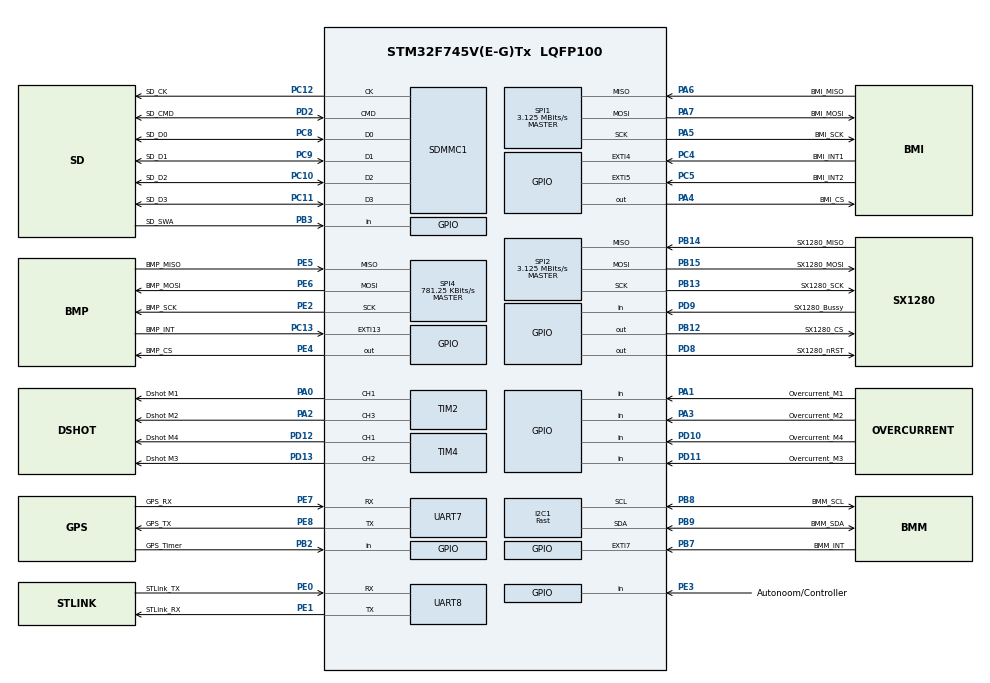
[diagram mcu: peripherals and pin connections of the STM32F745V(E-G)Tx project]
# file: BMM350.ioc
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CORTEX_M7.default_mode_Activation=1
Dma.Request0=TIM4_CH1
Dma.Request1=TIM4_CH2
Dma.Request2=TIM2_UP/CH3
Dma.Request3=TIM2_CH1
Dma.TIM2_CH1.3.Direction=DMA_MEMORY_TO_PERIPH
Dma.TIM2_CH1.3.FIFOMode=DMA_FIFOMODE_DISABLE
Dma.TIM2_CH1.3.Instance=DMA1_Stream5
Dma.TIM2_CH1.3.MemDataAlignment=DMA_MDATAALIGN_WORD
Dma.TIM2_CH1.3.MemInc=DMA_MINC_ENABLE
Dma.TIM2_CH1.3.Mode=DMA_NORMAL
Dma.TIM2_CH1.3.PeriphDataAlignment=DMA_PDATAALIGN_WORD
Dma.TIM2_CH1.3.PeriphInc=DMA_PINC_DISABLE
Dma.TIM2_CH1.3.Priority=DMA_PRIORITY_VERY_HIGH
Dma.TIM2_UP/CH3.2.Direction=DMA_MEMORY_TO_PERIPH
Dma.TIM2_UP/CH3.2.FIFOMode=DMA_FIFOMODE_DISABLE
Dma.TIM2_UP/CH3.2.Instance=DMA1_Stream1
Dma.TIM2_UP/CH3.2.MemDataAlignment=DMA_MDATAALIGN_WORD
Dma.TIM2_UP/CH3.2.MemInc=DMA_MINC_ENABLE
Dma.TIM2_UP/CH3.2.Mode=DMA_NORMAL
Dma.TIM2_UP/CH3.2.PeriphDataAlignment=DMA_PDATAALIGN_WORD
Dma.TIM2_UP/CH3.2.PeriphInc=DMA_PINC_DISABLE
Dma.TIM2_UP/CH3.2.Priority=DMA_PRIORITY_VERY_HIGH
Dma.TIM4_CH1.0.Direction=DMA_MEMORY_TO_PERIPH
Dma.TIM4_CH1.0.FIFOMode=DMA_FIFOMODE_DISABLE
Dma.TIM4_CH1.0.Instance=DMA1_Stream0
Dma.TIM4_CH1.0.MemDataAlignment=DMA_MDATAALIGN_HALFWORD
Dma.TIM4_CH1.0.MemInc=DMA_MINC_ENABLE
Dma.TIM4_CH1.0.Mode=DMA_NORMAL
Dma.TIM4_CH1.0.PeriphDataAlignment=DMA_PDATAALIGN_HALFWORD
Dma.TIM4_CH1.0.PeriphInc=DMA_PINC_DISABLE
Dma.TIM4_CH1.0.Priority=DMA_PRIORITY_VERY_HIGH
Dma.TIM4_CH2.1.Direction=DMA_MEMORY_TO_PERIPH
Dma.TIM4_CH2.1.FIFOMode=DMA_FIFOMODE_DISABLE
Dma.TIM4_CH2.1.Instance=DMA1_Stream3
Dma.TIM4_CH2.1.MemDataAlignment=DMA_MDATAALIGN_HALFWORD
Dma.TIM4_CH2.1.MemInc=DMA_MINC_ENABLE
Dma.TIM4_CH2.1.Mode=DMA_NORMAL
Dma.TIM4_CH2.1.PeriphDataAlignment=DMA_PDATAALIGN_HALFWORD
Dma.TIM4_CH2.1.PeriphInc=DMA_PINC_DISABLE
Dma.TIM4_CH2.1.Priority=DMA_PRIORITY_VERY_HIGH
FATFS.BSP.number=1
FATFS0.BSP.STBoard=false
FATFS0.BSP.api=Unknown
FATFS0.BSP.instance=PB3
FATFS0.BSP.ip=GPIO
FATFS0.BSP.mode=Input
FATFS0.BSP.name=Detect_SDIO
FATFS0.BSP.solution=PB3
I2C1.I2C_Speed_Mode=I2C_Fast
I2C1.Timing=0x00000108
Mcu.Family=STM32F7
Mcu.Name=STM32F745V(E-G)Tx
Mcu.Package=LQFP100
NVIC.DMA1_Stream0_IRQn=true\:0\:0\:false\:false\:true\:false\:true\:true
NVIC.DMA1_Stream1_IRQn=true\:0\:0\:false\:false\:true\:false\:true\:true
NVIC.DMA1_Stream3_IRQn=true\:0\:0\:false\:false\:true\:false\:true\:true
NVIC.DMA1_Stream5_IRQn=true\:0\:0\:false\:false\:true\:false\:true\:true
NVIC.EXTI15_10_IRQn=true\:0\:0\:false\:false\:true\:true\:true\:true
NVIC.EXTI4_IRQn=true\:3\:0\:true\:false\:true\:true\:true\:true
NVIC.EXTI9_5_IRQn=true\:3\:0\:true\:false\:true\:true\:true\:true
NVIC.PriorityGroup=NVIC_PRIORITYGROUP_4
PA0/WKUP.GPIO_Label=Dshot M1
PA0/WKUP.Signal=S_TIM2_CH1_ETR
PA1.GPIO_Label=Overcurrent_M1
PA1.Signal=GPIO_Input
PA13.GPIO_Label=STLink_DIO
PA13.Mode=Serial_Wire
PA13.Signal=SYS_JTMS-SWDIO
PA14.GPIO_Label=STLink_CLK
PA14.Mode=Serial_Wire
PA14.Signal=SYS_JTCK-SWCLK
PA2.GPIO_Label=Dshot M2
PA2.Signal=S_TIM2_CH3
PA3.GPIO_Label=Overcurrent_M2
PA3.Signal=GPIO_Input
PA4.GPIO_Label=BMI_CS
PA4.Signal=GPIO_Output
PA5.GPIO_Label=BMI_SCK
PA5.Mode=Full_Duplex_Master
PA5.Signal=SPI1_SCK
PA6.GPIO_Label=BMI_MISO
PA6.Mode=Full_Duplex_Master
PA6.Signal=SPI1_MISO
PA7.GPIO_Label=BMI_MOSI
PA7.Mode=Full_Duplex_Master
PA7.Signal=SPI1_MOSI
PB12.GPIO_Label=SX1280_CS
PB12.Signal=GPIO_Output
PB13.GPIO_Label=SX1280_SCK
PB13.Mode=Full_Duplex_Master
PB13.Signal=SPI2_SCK
PB14.GPIO_Label=SX1280_MISO
PB14.Mode=Full_Duplex_Master
PB14.Signal=SPI2_MISO
PB15.GPIO_Label=SX1280_MOSI
PB15.Mode=Full_Duplex_Master
PB15.Signal=SPI2_MOSI
PB2.GPIO_Label=GPS_Timer
PB2.Signal=GPIO_Input
PB3.GPIO_Label=SD_SWA
PB3.Signal=GPIO_Input
PB7.GPIO_Label=BMM_INT
PB7.Signal=GPXTI7
PB8.GPIO_Label=BMM_SCL
PB8.Mode=I2C
PB8.Signal=I2C1_SCL
PB9.GPIO_Label=BMM_SDA
PB9.Mode=I2C
PB9.Signal=I2C1_SDA
PC10.GPIO_Label=SD_D2
PC10.Mode=SD_4_bits_Wide_bus
PC10.Signal=SDMMC1_D2
PC11.GPIO_Label=SD_D3
PC11.Mode=SD_4_bits_Wide_bus
PC11.Signal=SDMMC1_D3
PC12.GPIO_Label=SD_CK
PC12.Mode=SD_4_bits_Wide_bus
PC12.Signal=SDMMC1_CK
PC13.GPIO_Label=BMP_INT
PC13.Signal=GPXTI13
PC4.GPIO_Label=BMI_INT1
PC4.Signal=GPXTI4
PC5.GPIO_Label=BMI_INT2
PC5.Signal=GPXTI5
PC8.GPIO_Label=SD_D0
PC8.Mode=SD_4_bits_Wide_bus
PC8.Signal=SDMMC1_D0
PC9.GPIO_Label=SD_D1
PC9.Mode=SD_4_bits_Wide_bus
PC9.Signal=SDMMC1_D1
PD10.GPIO_Label=Overcurrent_M4
PD10.Signal=GPIO_Input
PD11.GPIO_Label=Overcurrent_M3
PD11.Signal=GPIO_Input
PD12.GPIO_Label=Dshot M4
PD12.Signal=S_TIM4_CH1
PD13.GPIO_Label=Dshot M3
PD13.Signal=S_TIM4_CH2
PD2.GPIO_Label=SD_CMD
PD2.Mode=SD_4_bits_Wide_bus
PD2.Signal=SDMMC1_CMD
PD8.GPIO_Label=SX1280_nRST
PD8.Signal=GPIO_Output
PD9.GPIO_Label=SX1280_Bussy
PD9.Signal=GPIO_Input
PE0.GPIO_Label=STLink_TX
PE0.Mode=Asynchronous
PE0.Signal=UART8_RX
PE1.GPIO_Label=STLink_RX
PE1.Mode=Asynchronous
PE1.Signal=UART8_TX
PE2.GPIO_Label=BMP_SCK
PE2.Mode=Full_Duplex_Master
PE2.Signal=SPI4_SCK
PE3.GPIO_Label=Autonoom/Controller
PE3.Signal=GPIO_Input
PE4.GPIO_Label=BMP_CS
PE4.Signal=GPIO_Output
PE5.GPIO_Label=BMP_MISO
PE5.Mode=Full_Duplex_Master
PE5.Signal=SPI4_MISO
PE6.GPIO_Label=BMP_MOSI
PE6.Mode=Full_Duplex_Master
PE6.Signal=SPI4_MOSI
PE7.GPIO_Label=GPS_RX
PE7.Mode=Asynchronous
PE7.Signal=UART7_RX
PE8.GPIO_Label=GPS_TX
PE8.Mode=Asynchronous
PE8.Signal=UART7_TX
PH0/OSC_IN.Mode=HSE-External-Oscillator
PH0/OSC_IN.Signal=RCC_OSC_IN
PH1/OSC_OUT.Mode=HSE-External-Oscillator
PH1/OSC_OUT.Signal=RCC_OSC_OUT
ProjectManager.HeapSize=0x200
ProjectManager.StackSize=0x400
ProjectManager.TargetToolchain=STM32CubeIDE
RCC.AHBFreq_Value=100000000
RCC.APB1CLKDivider=RCC_HCLK_DIV16
RCC.APB1Freq_Value=6250000
RCC.APB1TimFreq_Value=12500000
RCC.APB2CLKDivider=RCC_HCLK_DIV16
RCC.APB2Freq_Value=6250000
RCC.APB2TimFreq_Value=12500000
RCC.CortexFreq_Value=100000000
RCC.HCLKFreq_Value=100000000
RCC.HSE_VALUE=16000000
RCC.HSI_VALUE=16000000
RCC.LSE_VALUE=32768
RCC.PLLM=8
RCC.PLLN=100
RCC.PLLQ=4
RCC.PLLSourceVirtual=RCC_PLLSOURCE_HSE
RCC.SDMMCClockSelection=RCC_SDMMC1CLKSOURCE_CLK48
RCC.SYSCLKFreq_VALUE=100000000
RCC.SYSCLKSource=RCC_SYSCLKSOURCE_PLLCLK
RCC.USBFreq_Value=50000000
RCC.VCOOutputFreq_Value=200000000
SDMMC1.ClockBypass=SDMMC_CLOCK_BYPASS_DISABLE
SH.S_TIM2_CH1_ETR.0=TIM2_CH1,PWM Generation1 CH1
SH.S_TIM2_CH3.0=TIM2_CH3,PWM Generation3 CH3
SH.S_TIM4_CH1.0=TIM4_CH1,PWM Generation1 CH1
SH.S_TIM4_CH2.0=TIM4_CH2,PWM Generation2 CH2
SPI1.CLKPhase=SPI_PHASE_2EDGE
SPI1.CLKPolarity=SPI_POLARITY_HIGH
SPI1.CalculateBaudRate=3.125 MBits/s
SPI1.DataSize=SPI_DATASIZE_8BIT
SPI1.Direction=SPI_DIRECTION_2LINES
SPI1.Mode=SPI_MODE_MASTER
SPI1.VirtualType=VM_MASTER
SPI2.BaudRatePrescaler=SPI_BAUDRATEPRESCALER_2
SPI2.CalculateBaudRate=3.125 MBits/s
SPI2.DataSize=SPI_DATASIZE_8BIT
SPI2.Direction=SPI_DIRECTION_2LINES
SPI2.Mode=SPI_MODE_MASTER
SPI2.NSSPMode=SPI_NSS_PULSE_DISABLE
SPI2.VirtualType=VM_MASTER
SPI4.BaudRatePrescaler=SPI_BAUDRATEPRESCALER_8
SPI4.CLKPhase=SPI_PHASE_1EDGE
SPI4.CLKPolarity=SPI_POLARITY_LOW
SPI4.CalculateBaudRate=781.25 KBits/s
SPI4.DataSize=SPI_DATASIZE_8BIT
SPI4.Direction=SPI_DIRECTION_2LINES
SPI4.Mode=SPI_MODE_MASTER
SPI4.VirtualType=VM_MASTER
TIM2.Channel-PWM\ Generation1\ CH1=TIM_CHANNEL_1
TIM2.Channel-PWM\ Generation3\ CH3=TIM_CHANNEL_3
TIM4.Channel-PWM\ Generation1\ CH1=TIM_CHANNEL_1
TIM4.Channel-PWM\ Generation2\ CH2=TIM_CHANNEL_2
VP_FATFS_VS_SDIO.Mode=SDIO
board=custom

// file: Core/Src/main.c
/* USER CODE BEGIN Header */
/**
  ******************************************************************************
  * @file           : main.c
  * @brief          : Main program body
  ******************************************************************************
  * @attention
  *
  * Copyright (c) 2026 STMicroelectronics.
  * All rights reserved.
  *
  * This software is licensed under terms that can be found in the LICENSE file
  * in the root directory of this software component.
  * If no LICENSE file comes with this software, it is provided AS-IS.
  *
  ******************************************************************************
  */
/* USER CODE END Header */
#include "main.h"
#include "fatfs.h"

/* USER CODE BEGIN Includes */
#include "stdio.h"
#include "bmm350.h"
#include "bmm350_oor.h"
#include "bmm350_defs.h"
//#include "BMM350.h"
//#include "BMI330.h"
//#include "pid_regulator.h"
/* USER CODE END Includes */

I2C_HandleTypeDef hi2c1;

SD_HandleTypeDef hsd1;

SPI_HandleTypeDef hspi1;
SPI_HandleTypeDef hspi2;
SPI_HandleTypeDef hspi4;

TIM_HandleTypeDef htim2;
TIM_HandleTypeDef htim4;
DMA_HandleTypeDef hdma_tim2_up_ch3;
DMA_HandleTypeDef hdma_tim2_ch1;
DMA_HandleTypeDef hdma_tim4_ch1;
DMA_HandleTypeDef hdma_tim4_ch2;

UART_HandleTypeDef huart7;
UART_HandleTypeDef huart8;

/* USER CODE BEGIN PV */
//BMP384_Calib calibData;
struct bmm350_dev dev;
struct bmm350_raw_mag_data raw_data;
struct bmm350_mag_temp_data comp_data;
struct bmm350_self_test test;

/*
PID_Handle_t struct_PidRateRoll;
PID_Handle_t struct_PidRatePitch;
PID_Handle_t struct_PidRateYaw;
BMM350_MagData BMM350_Data;
BMI330_Frame current_data;
*/

float g_hoogte;
float g_druk;
float g_hoek;
int g_acc;
int g_gyr;
float alpha = 0.98; // hoe hoger hoe meer de acc gaat doortellen
float dt = 0.02;   // voor 50hz
float gefilterde_hoogte = 0;
float verticale_snelheid = 0;
/* USER CODE END PV */

void SystemClock_Config(void);
static void MPU_Config(void);
static void MX_GPIO_Init(void);
static void MX_DMA_Init(void);
static void MX_I2C1_Init(void);
static void MX_SDMMC1_SD_Init(void);
static void MX_SPI1_Init(void);
static void MX_SPI2_Init(void);
static void MX_SPI4_Init(void);
static void MX_TIM2_Init(void);
static void MX_TIM4_Init(void);
static void MX_UART7_Init(void);
static void MX_UART8_Init(void);

/* USER CODE BEGIN 0 */

volatile int g_new_pressure_data = 0;

int _write(int file, char *ptr, int len) {
	for(int i = 0; i < len; i++){
		if(ptr[i]=='\n'){
			HAL_UART_Transmit(&huart8, (uint8_t*)"\r", 1, HAL_MAX_DELAY);
		}
		HAL_UART_Transmit(&huart8, (uint8_t*)&ptr[i], 1, HAL_MAX_DELAY);
	}
    return len;
}
/*
void Update_Altitude_Filter(float baro_hoogte, float acc_z_m_s2) {
    verticale_snelheid += acc_z_m_s2 * dt;
    float voorspelde_hoogte = gefilterde_hoogte + (verticale_snelheid * dt);
    gefilterde_hoogte = (alpha * voorspelde_hoogte) + ((1 - alpha) * baro_hoogte);
}
*/
/* USER CODE BEGIN 0 */
BMM350_INTF_RET_TYPE stm32_i2c_read(uint8_t reg_addr, uint8_t *reg_data, uint32_t len, void *intf_ptr) {
    uint8_t dev_addr = *(uint8_t*)intf_ptr;
    if (HAL_I2C_Mem_Read(&hi2c1, dev_addr, reg_addr, I2C_MEMADD_SIZE_8BIT, reg_data, len, 100) == HAL_OK) {
        return BMM350_OK;
    }
    return BMM350_E_COM_FAIL;
}

BMM350_INTF_RET_TYPE stm32_i2c_write(uint8_t reg_addr, const uint8_t *reg_data, uint32_t len, void *intf_ptr) {
    uint8_t dev_addr = *(uint8_t*)intf_ptr;
    if (HAL_I2C_Mem_Write(&hi2c1, dev_addr, reg_addr, I2C_MEMADD_SIZE_8BIT, (uint8_t*)reg_data, len, 100) == HAL_OK) {
        return BMM350_OK;
    }
    return BMM350_E_COM_FAIL;
}

void stm32_delay_us(uint32_t period, void *intf_ptr) {
    // STM32 werkt in milliseconden, Bosch vraagt microseconden
    HAL_Delay((period / 1000) + 1);
}
/* USER CODE END 0 */
/* USER CODE END 0 */

int main(void)
{

  /* MPU Configuration--------------------------------------------------------*/
  MPU_Config();

  /* MCU Configuration--------------------------------------------------------*/

  /* Reset of all peripherals, Initializes the Flash interface and the Systick. */
  HAL_Init();

  /* USER CODE BEGIN Init */
 /* Init_RateLoops();
  BMM350_Init();
  PID_HandleInit(struct_PidRateRoll);
  PID_HandleInit(struct_PidRatePitch);
  PID_HandleInit(struct_PidRateYaw);
  */
  //BMI330_Init();
  /* USER CODE END Init */

  /* Configure the system clock */
  SystemClock_Config();

  /* Initialize all configured peripherals */
  MX_GPIO_Init();
  MX_DMA_Init();
  MX_I2C1_Init();
  MX_SDMMC1_SD_Init();
  MX_SPI1_Init();
  MX_SPI2_Init();
  MX_SPI4_Init();
  MX_TIM2_Init();
  MX_TIM4_Init();
  MX_UART7_Init();
  MX_FATFS_Init();
  MX_UART8_Init();
  /* USER CODE BEGIN 2 */

    // 3. Start de Bosch Initialisatie
    int returnwaarde = bmm350_init(&dev);

    if (returnwaarde == BMM350_OK) {
        printf("Init succesvol!\n");
    } else {
        printf("Init gefaald, error code: %d\n", returnwaarde);
        while(1) { HAL_Delay(100); } // Blokkeer hier als het misgaat
    }

    // 4. Instellingen toepassen
    bmm350_set_powermode(BMM350_NORMAL_MODE, &dev);
    bmm350_set_odr_performance(BMM350_DATA_RATE_50HZ, BMM350_NO_AVERAGING, &dev);
    bmm350_enable_axes(BMM350_X_EN, BMM350_Y_EN, BMM350_Z_EN, &dev);

  //BMP384_Init(&calibData);
  uint8_t bmm350_adres = (0x14 << 1); // Gaat uit van ADSEL aan GND
  uint8_t buffer[3] = {0}; // Array voor: dummy1, dummy2, echte_data
  uint8_t chip_id = 0;
  uint8_t pData;

  // We lezen nu 3 bytes vanaf register 0x00
  HAL_StatusTypeDef status = HAL_I2C_Mem_Read(&hi2c1, bmm350_adres, 0x00, I2C_MEMADD_SIZE_8BIT, buffer, 3, 100);
  uint8_t data[3];
  	HAL_I2C_Master_Transmit(&hi2c1, (0x14 << 1), 0x00, 1, 100);
  	HAL_I2C_Master_Receive(&hi2c1, (0x14 << 1), data, 3, 100);	// we lezen de 2 dummy bytes in + de goeie byte

  	for(int i = 0; i < 1; i++) {
  		pData = data[i + 2];	// we zetten hier de goeie byte in een nieuwe var
  	}
  	chip_id = pData;
  if (status == HAL_OK) {
      chip_id = buffer[2]; // Negeer de twee 0x00 dummy bytes!

      if (chip_id == 0x33) {
    	  printf("Communicatie en id zijn juist\n");
    	            HAL_Delay(5000);
      } else {
          printf("Communicatie maar foute id\n");
          HAL_Delay(5000);
      }
  } else {
	  HAL_StatusTypeDef status = HAL_I2C_Mem_Read(&hi2c1, bmm350_adres, 0x00, I2C_MEMADD_SIZE_8BIT, buffer, 3, 100);
	    uint8_t data[3];
	    	HAL_I2C_Master_Transmit(&hi2c1, (0x14 << 1), 0x00, 1, 100);
	    	HAL_I2C_Master_Receive(&hi2c1, (0x14 << 1), data, 3, 100);	// we lezen de 2 dummy bytes in + de goeie byte

	    	for(int i = 0; i < 1; i++) {
	    		pData = data[i + 2];	// we zetten hier de goeie byte in een nieuwe var
	    	}
	    	chip_id = pData;
	  printf("Eerste test is fout gegaan, ID: %d\n", chip_id);
	  printf("Status is %d", status);
	  HAL_Delay(4000);
	  int returnwaarde  = bmm350_init(&dev);
	    while(returnwaarde != 0){
	  	  returnwaarde = bmm350_init(&dev);
	  	printf("Tweede test is fout gegaan, ID: %d\n", chip_id);
	  		  HAL_Delay(4000);
	    };
      // FOUT! status is geen HAL_OK. Nu is er wél iets mis met de hardware.
  }
  HAL_Delay(4000);
  printf("Init klaar \n");
  bmm350_set_powermode(BMM350_NORMAL_MODE, &dev);
  bmm350_set_odr_performance(BMM350_DATA_RATE_50HZ, BMM350_NO_AVERAGING, &dev);
  bmm350_enable_axes(BMM350_X_EN, BMM350_Y_EN, BMM350_Z_EN, &dev);
  bmm350_enable_interrupt(BMM350_ENABLE_INTERRUPT, &dev);
  bmm350_configure_interrupt(BMM350_PULSED , BMM350_ACTIVE_HIGH , BMM350_INTR_PUSH_PULL , BMM350_MAP_TO_PIN, &dev);
  bmm350_read_uncomp_mag_temp_data(&raw_data, &dev);
  bmm350_set_int_ctrl_ibi(BMM350_IBI_ENABLE, BMM350_CLEAR_ON_IBI, &dev);
  bmm350_get_compensated_mag_xyz_temp_data(&comp_data, &dev);
  bmm350_perform_self_test(&test, &dev);
  bmm350_set_i2c_wdt(BMM350_I2C_WDT_DIS, BMM350_I2C_WDT_SEL_SHORT , &dev);
  /* USER CODE END 2 */

  /* Infinite loop */
  /* USER CODE BEGIN WHILE */
  while (1)
  {
	  bmm350_read_uncomp_mag_temp_data(&raw_data, &dev);
	  printf("Raw Data: X: %lu, Y: %lu, Z: %lu, Extra: %lu\n", raw_data.raw_xdata, raw_data.raw_ydata, raw_data.raw_zdata, raw_data.raw_data_t);
	  bmm350_get_compensated_mag_xyz_temp_data(&comp_data, &dev);
	  printf("Comp Data: X: %f, Y: %f, Z: %f, temp: %f\n", comp_data.x, comp_data.y, comp_data.z, comp_data.temperature);
	  bmm350_perform_self_test(&test, &dev);
	  printf("Comp Data: X: %f, XH: %f, XL: %f, Y: %f, YH: %f, YL: %f\n", test.out_ust_x, test.out_ust_xh, test.out_ust_xl, test.out_ust_y, test.out_ust_yh, test.out_ust_yl);

    /* USER CODE END WHILE */

  }
}

void SystemClock_Config(void)
{
  RCC_OscInitTypeDef RCC_OscInitStruct = {0};
  RCC_ClkInitTypeDef RCC_ClkInitStruct = {0};

  /** Configure the main internal regulator output voltage
  */
  __HAL_RCC_PWR_CLK_ENABLE();
  __HAL_PWR_VOLTAGESCALING_CONFIG(PWR_REGULATOR_VOLTAGE_SCALE3);

  /** Initializes the RCC Oscillators according to the specified parameters
  * in the RCC_OscInitTypeDef structure.
  */
  RCC_OscInitStruct.OscillatorType = RCC_OSCILLATORTYPE_HSE;
  RCC_OscInitStruct.HSEState = RCC_HSE_ON;
  RCC_OscInitStruct.PLL.PLLState = RCC_PLL_ON;
  RCC_OscInitStruct.PLL.PLLSource = RCC_PLLSOURCE_HSE;
  RCC_OscInitStruct.PLL.PLLM = 8;
  RCC_OscInitStruct.PLL.PLLN = 50;
  RCC_OscInitStruct.PLL.PLLP = RCC_PLLP_DIV2;
  RCC_OscInitStruct.PLL.PLLQ = 2;
  if (HAL_RCC_OscConfig(&RCC_OscInitStruct) != HAL_OK)
  {
    Error_Handler();
  }

  /** Activate the Over-Drive mode
  */
  if (HAL_PWREx_EnableOverDrive() != HAL_OK)
  {
    Error_Handler();
  }

  /** Initializes the CPU, AHB and APB buses clocks
  */
  RCC_ClkInitStruct.ClockType = RCC_CLOCKTYPE_HCLK|RCC_CLOCKTYPE_SYSCLK
                              |RCC_CLOCKTYPE_PCLK1|RCC_CLOCKTYPE_PCLK2;
  RCC_ClkInitStruct.SYSCLKSource = RCC_SYSCLKSOURCE_PLLCLK;
  RCC_ClkInitStruct.AHBCLKDivider = RCC_SYSCLK_DIV1;
  RCC_ClkInitStruct.APB1CLKDivider = RCC_HCLK_DIV1;
  RCC_ClkInitStruct.APB2CLKDivider = RCC_HCLK_DIV1;

  if (HAL_RCC_ClockConfig(&RCC_ClkInitStruct, FLASH_LATENCY_1) != HAL_OK)
  {
    Error_Handler();
  }
}

static void MX_I2C1_Init(void)
{

  hi2c1.Instance = I2C1;
  hi2c1.Init.Timing = 0x00401959;
  hi2c1.Init.OwnAddress1 = 0;
  hi2c1.Init.AddressingMode = I2C_ADDRESSINGMODE_7BIT;
  hi2c1.Init.DualAddressMode = I2C_DUALADDRESS_DISABLE;
  hi2c1.Init.OwnAddress2 = 0;
  hi2c1.Init.OwnAddress2Masks = I2C_OA2_NOMASK;
  hi2c1.Init.GeneralCallMode = I2C_GENERALCALL_DISABLE;
  hi2c1.Init.NoStretchMode = I2C_NOSTRETCH_DISABLE;
  if (HAL_I2C_Init(&hi2c1) != HAL_OK)
  {
    Error_Handler();
  }

  /** Configure Analogue filter
  */
  if (HAL_I2CEx_ConfigAnalogFilter(&hi2c1, I2C_ANALOGFILTER_ENABLE) != HAL_OK)
  {
    Error_Handler();
  }

  /** Configure Digital filter
  */
  if (HAL_I2CEx_ConfigDigitalFilter(&hi2c1, 0) != HAL_OK)
  {
    Error_Handler();
  }

}

static void MX_SDMMC1_SD_Init(void)
{

  hsd1.Instance = SDMMC1;
  hsd1.Init.ClockEdge = SDMMC_CLOCK_EDGE_RISING;
  hsd1.Init.ClockBypass = SDMMC_CLOCK_BYPASS_DISABLE;
  hsd1.Init.ClockPowerSave = SDMMC_CLOCK_POWER_SAVE_DISABLE;
  hsd1.Init.BusWide = SDMMC_BUS_WIDE_1B;
  hsd1.Init.HardwareFlowControl = SDMMC_HARDWARE_FLOW_CONTROL_DISABLE;
  hsd1.Init.ClockDiv = 0;

}

static void MX_SPI1_Init(void)
{

  /* SPI1 parameter configuration*/
  hspi1.Instance = SPI1;
  hspi1.Init.Mode = SPI_MODE_MASTER;
  hspi1.Init.Direction = SPI_DIRECTION_2LINES;
  hspi1.Init.DataSize = SPI_DATASIZE_8BIT;
  hspi1.Init.CLKPolarity = SPI_POLARITY_HIGH;
  hspi1.Init.CLKPhase = SPI_PHASE_2EDGE;
  hspi1.Init.NSS = SPI_NSS_SOFT;
  hspi1.Init.BaudRatePrescaler = SPI_BAUDRATEPRESCALER_2;
  hspi1.Init.FirstBit = SPI_FIRSTBIT_MSB;
  hspi1.Init.TIMode = SPI_TIMODE_DISABLE;
  hspi1.Init.CRCCalculation = SPI_CRCCALCULATION_DISABLE;
  hspi1.Init.CRCPolynomial = 7;
  hspi1.Init.CRCLength = SPI_CRC_LENGTH_DATASIZE;
  hspi1.Init.NSSPMode = SPI_NSS_PULSE_DISABLE;
  if (HAL_SPI_Init(&hspi1) != HAL_OK)
  {
    Error_Handler();
  }

}

static void MX_SPI2_Init(void)
{

  /* SPI2 parameter configuration*/
  hspi2.Instance = SPI2;
  hspi2.Init.Mode = SPI_MODE_MASTER;
  hspi2.Init.Direction = SPI_DIRECTION_2LINES;
  hspi2.Init.DataSize = SPI_DATASIZE_8BIT;
  hspi2.Init.CLKPolarity = SPI_POLARITY_LOW;
  hspi2.Init.CLKPhase = SPI_PHASE_1EDGE;
  hspi2.Init.NSS = SPI_NSS_SOFT;
  hspi2.Init.BaudRatePrescaler = SPI_BAUDRATEPRESCALER_2;
  hspi2.Init.FirstBit = SPI_FIRSTBIT_MSB;
  hspi2.Init.TIMode = SPI_TIMODE_DISABLE;
  hspi2.Init.CRCCalculation = SPI_CRCCALCULATION_DISABLE;
  hspi2.Init.CRCPolynomial = 7;
  hspi2.Init.CRCLength = SPI_CRC_LENGTH_DATASIZE;
  hspi2.Init.NSSPMode = SPI_NSS_PULSE_DISABLE;
  if (HAL_SPI_Init(&hspi2) != HAL_OK)
  {
    Error_Handler();
  }

}

static void MX_SPI4_Init(void)
{

  /* SPI4 parameter configuration*/
  hspi4.Instance = SPI4;
  hspi4.Init.Mode = SPI_MODE_MASTER;
  hspi4.Init.Direction = SPI_DIRECTION_2LINES;
  hspi4.Init.DataSize = SPI_DATASIZE_8BIT;
  hspi4.Init.CLKPolarity = SPI_POLARITY_LOW;
  hspi4.Init.CLKPhase = SPI_PHASE_1EDGE;
  hspi4.Init.NSS = SPI_NSS_SOFT;
  hspi4.Init.BaudRatePrescaler = SPI_BAUDRATEPRESCALER_8;
  hspi4.Init.FirstBit = SPI_FIRSTBIT_MSB;
  hspi4.Init.TIMode = SPI_TIMODE_DISABLE;
  hspi4.Init.CRCCalculation = SPI_CRCCALCULATION_DISABLE;
  hspi4.Init.CRCPolynomial = 7;
  hspi4.Init.CRCLength = SPI_CRC_LENGTH_DATASIZE;
  hspi4.Init.NSSPMode = SPI_NSS_PULSE_ENABLE;
  if (HAL_SPI_Init(&hspi4) != HAL_OK)
  {
    Error_Handler();
  }

}

static void MX_TIM2_Init(void)
{

  TIM_MasterConfigTypeDef sMasterConfig = {0};
  TIM_OC_InitTypeDef sConfigOC = {0};

  htim2.Instance = TIM2;
  htim2.Init.Prescaler = 0;
  htim2.Init.CounterMode = TIM_COUNTERMODE_UP;
  htim2.Init.Period = 4294967295;
  htim2.Init.ClockDivision = TIM_CLOCKDIVISION_DIV1;
  htim2.Init.AutoReloadPreload = TIM_AUTORELOAD_PRELOAD_DISABLE;
  if (HAL_TIM_PWM_Init(&htim2) != HAL_OK)
  {
    Error_Handler();
  }
  sMasterConfig.MasterOutputTrigger = TIM_TRGO_RESET;
  sMasterConfig.MasterSlaveMode = TIM_MASTERSLAVEMODE_DISABLE;
  if (HAL_TIMEx_MasterConfigSynchronization(&htim2, &sMasterConfig) != HAL_OK)
  {
    Error_Handler();
  }
  sConfigOC.OCMode = TIM_OCMODE_PWM1;
  sConfigOC.Pulse = 0;
  sConfigOC.OCPolarity = TIM_OCPOLARITY_HIGH;
  sConfigOC.OCFastMode = TIM_OCFAST_DISABLE;
  if (HAL_TIM_PWM_ConfigChannel(&htim2, &sConfigOC, TIM_CHANNEL_1) != HAL_OK)
  {
    Error_Handler();
  }
  if (HAL_TIM_PWM_ConfigChannel(&htim2, &sConfigOC, TIM_CHANNEL_3) != HAL_OK)
  {
    Error_Handler();
  }
  HAL_TIM_MspPostInit(&htim2);

}

static void MX_TIM4_Init(void)
{

  TIM_MasterConfigTypeDef sMasterConfig = {0};
  TIM_OC_InitTypeDef sConfigOC = {0};

  htim4.Instance = TIM4;
  htim4.Init.Prescaler = 0;
  htim4.Init.CounterMode = TIM_COUNTERMODE_UP;
  htim4.Init.Period = 65535;
  htim4.Init.ClockDivision = TIM_CLOCKDIVISION_DIV1;
  htim4.Init.AutoReloadPreload = TIM_AUTORELOAD_PRELOAD_DISABLE;
  if (HAL_TIM_PWM_Init(&htim4) != HAL_OK)
  {
    Error_Handler();
  }
  sMasterConfig.MasterOutputTrigger = TIM_TRGO_RESET;
  sMasterConfig.MasterSlaveMode = TIM_MASTERSLAVEMODE_DISABLE;
  if (HAL_TIMEx_MasterConfigSynchronization(&htim4, &sMasterConfig) != HAL_OK)
  {
    Error_Handler();
  }
  sConfigOC.OCMode = TIM_OCMODE_PWM1;
  sConfigOC.Pulse = 0;
  sConfigOC.OCPolarity = TIM_OCPOLARITY_HIGH;
  sConfigOC.OCFastMode = TIM_OCFAST_DISABLE;
  if (HAL_TIM_PWM_ConfigChannel(&htim4, &sConfigOC, TIM_CHANNEL_1) != HAL_OK)
  {
    Error_Handler();
  }
  if (HAL_TIM_PWM_ConfigChannel(&htim4, &sConfigOC, TIM_CHANNEL_2) != HAL_OK)
  {
    Error_Handler();
  }
  HAL_TIM_MspPostInit(&htim4);

}

static void MX_UART7_Init(void)
{

  huart7.Instance = UART7;
  huart7.Init.BaudRate = 115200;
  huart7.Init.WordLength = UART_WORDLENGTH_8B;
  huart7.Init.StopBits = UART_STOPBITS_1;
  huart7.Init.Parity = UART_PARITY_NONE;
  huart7.Init.Mode = UART_MODE_TX_RX;
  huart7.Init.HwFlowCtl = UART_HWCONTROL_NONE;
  huart7.Init.OverSampling = UART_OVERSAMPLING_16;
  huart7.Init.OneBitSampling = UART_ONE_BIT_SAMPLE_DISABLE;
  huart7.AdvancedInit.AdvFeatureInit = UART_ADVFEATURE_NO_INIT;
  if (HAL_UART_Init(&huart7) != HAL_OK)
  {
    Error_Handler();
  }

}

static void MX_UART8_Init(void)
{

  huart8.Instance = UART8;
  huart8.Init.BaudRate = 115200;
  huart8.Init.WordLength = UART_WORDLENGTH_8B;
  huart8.Init.StopBits = UART_STOPBITS_1;
  huart8.Init.Parity = UART_PARITY_NONE;
  huart8.Init.Mode = UART_MODE_TX_RX;
  huart8.Init.HwFlowCtl = UART_HWCONTROL_NONE;
  huart8.Init.OverSampling = UART_OVERSAMPLING_16;
  huart8.Init.OneBitSampling = UART_ONE_BIT_SAMPLE_DISABLE;
  huart8.AdvancedInit.AdvFeatureInit = UART_ADVFEATURE_NO_INIT;
  if (HAL_UART_Init(&huart8) != HAL_OK)
  {
    Error_Handler();
  }

}

static void MX_DMA_Init(void)
{

  /* DMA controller clock enable */
  __HAL_RCC_DMA1_CLK_ENABLE();

  /* DMA interrupt init */
  /* DMA1_Stream0_IRQn interrupt configuration */
  HAL_NVIC_SetPriority(DMA1_Stream0_IRQn, 0, 0);
  HAL_NVIC_EnableIRQ(DMA1_Stream0_IRQn);
  /* DMA1_Stream1_IRQn interrupt configuration */
  HAL_NVIC_SetPriority(DMA1_Stream1_IRQn, 0, 0);
  HAL_NVIC_EnableIRQ(DMA1_Stream1_IRQn);
  /* DMA1_Stream3_IRQn interrupt configuration */
  HAL_NVIC_SetPriority(DMA1_Stream3_IRQn, 0, 0);
  HAL_NVIC_EnableIRQ(DMA1_Stream3_IRQn);
  /* DMA1_Stream5_IRQn interrupt configuration */
  HAL_NVIC_SetPriority(DMA1_Stream5_IRQn, 0, 0);
  HAL_NVIC_EnableIRQ(DMA1_Stream5_IRQn);

}

static void MX_GPIO_Init(void)
{
  GPIO_InitTypeDef GPIO_InitStruct = {0};

  /* GPIO Ports Clock Enable */
  __HAL_RCC_GPIOE_CLK_ENABLE();
  __HAL_RCC_GPIOC_CLK_ENABLE();
  __HAL_RCC_GPIOH_CLK_ENABLE();
  __HAL_RCC_GPIOA_CLK_ENABLE();
  __HAL_RCC_GPIOB_CLK_ENABLE();
  __HAL_RCC_GPIOD_CLK_ENABLE();

  /*Configure GPIO pin Output Level */
  HAL_GPIO_WritePin(BMP_CS_GPIO_Port, BMP_CS_Pin, GPIO_PIN_RESET);

  /*Configure GPIO pin Output Level */
  HAL_GPIO_WritePin(BMI_CS_GPIO_Port, BMI_CS_Pin, GPIO_PIN_RESET);

  /*Configure GPIO pin Output Level */
  HAL_GPIO_WritePin(SX1280_CS_GPIO_Port, SX1280_CS_Pin, GPIO_PIN_RESET);

  /*Configure GPIO pin Output Level */
  HAL_GPIO_WritePin(SX1280_nRST_GPIO_Port, SX1280_nRST_Pin, GPIO_PIN_RESET);

  /*Configure GPIO pin : Autonoom_Controller_Pin */
  GPIO_InitStruct.Pin = Autonoom_Controller_Pin;
  GPIO_InitStruct.Mode = GPIO_MODE_INPUT;
  GPIO_InitStruct.Pull = GPIO_NOPULL;
  HAL_GPIO_Init(Autonoom_Controller_GPIO_Port, &GPIO_InitStruct);

  /*Configure GPIO pin : BMP_CS_Pin */
  GPIO_InitStruct.Pin = BMP_CS_Pin;
  GPIO_InitStruct.Mode = GPIO_MODE_OUTPUT_PP;
  GPIO_InitStruct.Pull = GPIO_NOPULL;
  GPIO_InitStruct.Speed = GPIO_SPEED_FREQ_LOW;
  HAL_GPIO_Init(BMP_CS_GPIO_Port, &GPIO_InitStruct);

  /*Configure GPIO pins : BMP_INT_Pin BMI_INT1_Pin BMI_INT2_Pin */
  GPIO_InitStruct.Pin = BMP_INT_Pin|BMI_INT1_Pin|BMI_INT2_Pin;
  GPIO_InitStruct.Mode = GPIO_MODE_IT_RISING;
  GPIO_InitStruct.Pull = GPIO_NOPULL;
  HAL_GPIO_Init(GPIOC, &GPIO_InitStruct);

  /*Configure GPIO pins : Overcurrent_M1_Pin Overcurrent_M2_Pin */
  GPIO_InitStruct.Pin = Overcurrent_M1_Pin|Overcurrent_M2_Pin;
  GPIO_InitStruct.Mode = GPIO_MODE_INPUT;
  GPIO_InitStruct.Pull = GPIO_NOPULL;
  HAL_GPIO_Init(GPIOA, &GPIO_InitStruct);

  /*Configure GPIO pin : BMI_CS_Pin */
  GPIO_InitStruct.Pin = BMI_CS_Pin;
  GPIO_InitStruct.Mode = GPIO_MODE_OUTPUT_PP;
  GPIO_InitStruct.Pull = GPIO_NOPULL;
  GPIO_InitStruct.Speed = GPIO_SPEED_FREQ_LOW;
  HAL_GPIO_Init(BMI_CS_GPIO_Port, &GPIO_InitStruct);

  /*Configure GPIO pins : GPS_Timer_Pin SD_SWA_Pin */
  GPIO_InitStruct.Pin = GPS_Timer_Pin|SD_SWA_Pin;
  GPIO_InitStruct.Mode = GPIO_MODE_INPUT;
  GPIO_InitStruct.Pull = GPIO_NOPULL;
  HAL_GPIO_Init(GPIOB, &GPIO_InitStruct);

  /*Configure GPIO pin : SX1280_CS_Pin */
  GPIO_InitStruct.Pin = SX1280_CS_Pin;
  GPIO_InitStruct.Mode = GPIO_MODE_OUTPUT_PP;
  GPIO_InitStruct.Pull = GPIO_NOPULL;
  GPIO_InitStruct.Speed = GPIO_SPEED_FREQ_LOW;
  HAL_GPIO_Init(SX1280_CS_GPIO_Port, &GPIO_InitStruct);

  /*Configure GPIO pin : SX1280_nRST_Pin */
  GPIO_InitStruct.Pin = SX1280_nRST_Pin;
  GPIO_InitStruct.Mode = GPIO_MODE_OUTPUT_PP;
  GPIO_InitStruct.Pull = GPIO_NOPULL;
  GPIO_InitStruct.Speed = GPIO_SPEED_FREQ_LOW;
  HAL_GPIO_Init(SX1280_nRST_GPIO_Port, &GPIO_InitStruct);

  /*Configure GPIO pins : SX1280_Bussy_Pin Overcurrent_M4_Pin Overcurrent_M3_Pin */
  GPIO_InitStruct.Pin = SX1280_Bussy_Pin|Overcurrent_M4_Pin|Overcurrent_M3_Pin;
  GPIO_InitStruct.Mode = GPIO_MODE_INPUT;
  GPIO_InitStruct.Pull = GPIO_NOPULL;
  HAL_GPIO_Init(GPIOD, &GPIO_InitStruct);

  /*Configure GPIO pin : BMM_INT_Pin */
  GPIO_InitStruct.Pin = BMM_INT_Pin;
  GPIO_InitStruct.Mode = GPIO_MODE_IT_RISING;
  GPIO_InitStruct.Pull = GPIO_NOPULL;
  HAL_GPIO_Init(BMM_INT_GPIO_Port, &GPIO_InitStruct);

  /* EXTI interrupt init*/
  HAL_NVIC_SetPriority(EXTI4_IRQn, 3, 0);
  HAL_NVIC_EnableIRQ(EXTI4_IRQn);

  HAL_NVIC_SetPriority(EXTI9_5_IRQn, 3, 0);
  HAL_NVIC_EnableIRQ(EXTI9_5_IRQn);

  HAL_NVIC_SetPriority(EXTI15_10_IRQn, 0, 0);
  HAL_NVIC_EnableIRQ(EXTI15_10_IRQn);

}

/* USER CODE BEGIN 4 */
/*
void Update_Motors(uint16_t throttle, int16_t roll, int16_t pitch, int16_t yaw) {
    int16_t m1 = throttle + pitch + roll - yaw; // Linksvoor
    int16_t m2 = throttle + pitch - roll + yaw; // Rechtsvoor
    int16_t m3 = throttle - pitch + roll + yaw; // Linksachter
    int16_t m4 = throttle - pitch - roll - yaw; // Rechtsachter
}
*/
void HAL_GPIO_EXTI_Callback(uint16_t GPIO_Pin)
{
/*
    if (GPIO_Pin == GPIO_PIN_4)	//INT1 van BMI
    {
    	float data[15];
    	int len = 15;
    	float roll, pitch;
    	BMI330_ReadFIFO(data, len);
    	BMI330_ParseFIFOFrame(&data, &current_data);
    	BMI330_GetAngles(current_data, roll, pitch);

    	printf("Data van de BMI INT1 pin: \n");
    	printf("Gyro data: X = %f, Y = %f, Z = %f \n", current_data->gyr_x, current_data->gyr_y, current_data->gyr_z);
    	printf("acc  data: X = %f, Y = %f, Z = %f \n", current_data->acc_x, current_data->acc_y, current_data->acc_z);
    	printf("temp: %f \n\n\n\n", current_data->sensor_temp);
    	g_temp = current_data->sensor_temp;
    	g_roll = roll;
    	g_pitch = pitch;
    	return;
    }

    if (GPIO_Pin == GPIO_PIN_5)	//INT2 van BMI
    {
    	return;
    }
    if (GPIO_Pin == GPIO_PIN_7)	//INT van BMM350
    {
    	float roll, pitch;
    	BMI330_GetAngles(current_data, &roll, &pitch);
    	BMM350_GetData(&BMM350_Data, roll, pitch);
    	float hoek = BMM350_Data.richting;

    	// calibrate is iets wat we eenmalig moeten doen, hieruit halen we de vaste ofset waardes die we daarna kunnen gebruiken
    	BMM350_Calibrate(BMM350_Data.x, BMM350_Data.y, BMM350_Data.z, BMM350_Data.x_offset, BMM350_Data.y_offset, BMM350_Data.z_offset);
    	printf("BMM350 Data: \n");
    	printf("BMM350 Raw Data: x = %d, Y = %d, Z = %d \n\n", BMM350_Data.x, BMM350_Data.y, BMM350_Data.z);

    	// enkel de laatste offset meting is belangerijk want dan heb je de uiterste bereikt
    	printf("BMM350 offsets Data: x = %d, Y = %d, Z = %d \n\n\n\n", BMM350_Data.x_offset, BMM350_Data.y_offset, BMM350_Data.z_offset);

    	g_hoek = hoek;
    	return;
    }
    if (GPIO_Pin == GPIO_PIN_13) //INT van BMP
    {
    	float druk = BMP384_ReadData();
    	float hoogte = BMP384_CalculateAltitude(druk);

    	printf("BMP384 Data: \n");
    	printf("BMP druk = %f, hoogte = %f", druk, hoogte);
    	g_druk = druk;
    	g_hoogte = hoogte;
    	return;
    }
*/
	if (GPIO_Pin == GPIO_PIN_13)	//INT van BMP
    	{
			g_new_pressure_data = 1;
    		return;
    	}
}
/* USER CODE END 4 */

 /* MPU Configuration */

void MPU_Config(void)
{
  MPU_Region_InitTypeDef MPU_InitStruct = {0};

  /* Disables the MPU */
  HAL_MPU_Disable();

  /** Initializes and configures the Region and the memory to be protected
  */
  MPU_InitStruct.Enable = MPU_REGION_ENABLE;
  MPU_InitStruct.Number = MPU_REGION_NUMBER0;
  MPU_InitStruct.BaseAddress = 0x0;
  MPU_InitStruct.Size = MPU_REGION_SIZE_4GB;
  MPU_InitStruct.SubRegionDisable = 0x87;
  MPU_InitStruct.TypeExtField = MPU_TEX_LEVEL0;
  MPU_InitStruct.AccessPermission = MPU_REGION_NO_ACCESS;
  MPU_InitStruct.DisableExec = MPU_INSTRUCTION_ACCESS_DISABLE;
  MPU_InitStruct.IsShareable = MPU_ACCESS_SHAREABLE;
  MPU_InitStruct.IsCacheable = MPU_ACCESS_NOT_CACHEABLE;
  MPU_InitStruct.IsBufferable = MPU_ACCESS_NOT_BUFFERABLE;

  HAL_MPU_ConfigRegion(&MPU_InitStruct);
  /* Enables the MPU */
  HAL_MPU_Enable(MPU_PRIVILEGED_DEFAULT);

}

void Error_Handler(void)
{
  __disable_irq();
  while (1)
  {
  }
}
